One B-rep face of a CAD part: STEP entity #20.
In plain terms, the planar face has unit normal (1, 0, 0).
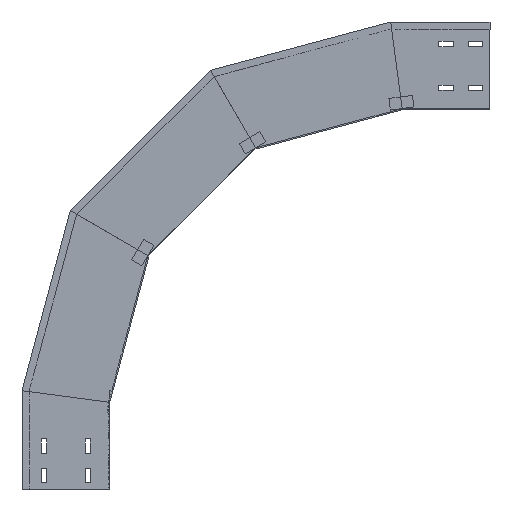
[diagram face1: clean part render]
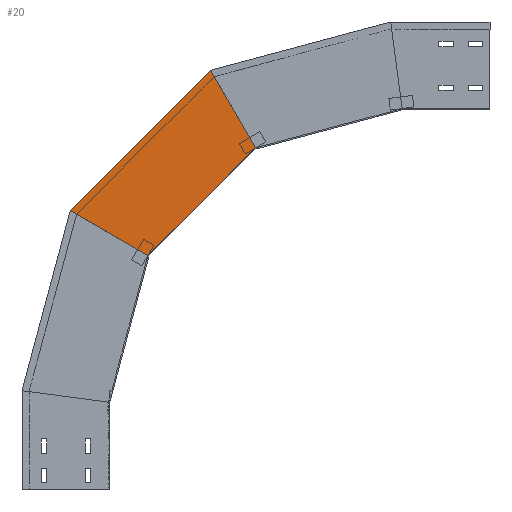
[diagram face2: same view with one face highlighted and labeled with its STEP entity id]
Its self-contained STEP definition (entity closure, numbers rounded to 3 decimals):
#20 = ADVANCED_FACE ( 'NONE', ( #899 ), #326, .T. ) ;
#69 = VECTOR ( 'NONE', #1328, 1000. ) ;
#89 = EDGE_CURVE ( 'NONE', #419, #1081, #347, .T. ) ;
#161 = CARTESIAN_POINT ( 'NONE',  ( 0., -129.979, 363.834 ) ) ;
#304 = CARTESIAN_POINT ( 'NONE',  ( 0., -250.175, 583.315 ) ) ;
#326 = PLANE ( 'NONE',  #1686 ) ;
#339 = DIRECTION ( 'NONE',  ( 1., 0., 0. ) ) ;
#347 = LINE ( 'NONE', #161, #1726 ) ;
#419 = VERTEX_POINT ( 'NONE', #2018 ) ;
#473 = EDGE_CURVE ( 'NONE', #1081, #1722, #1316, .T. ) ;
#825 = CARTESIAN_POINT ( 'NONE',  ( 0., -67.034, 400.175 ) ) ;
#899 = FACE_OUTER_BOUND ( 'NONE', #1931, .T. ) ;
#938 = ORIENTED_EDGE ( 'NONE', *, *, #89, .F. ) ;
#1081 = VERTEX_POINT ( 'NONE', #825 ) ;
#1151 = VECTOR ( 'NONE', #2013, 1000. ) ;
#1255 = EDGE_CURVE ( 'NONE', #419, #1511, #1787, .T. ) ;
#1316 = LINE ( 'NONE', #2109, #69 ) ;
#1328 = DIRECTION ( 'NONE',  ( 0., -0.707, 0.707 ) ) ;
#1434 = ORIENTED_EDGE ( 'NONE', *, *, #473, .F. ) ;
#1441 = CARTESIAN_POINT ( 'NONE',  ( 0., 70.365, 474.908 ) ) ;
#1498 = ORIENTED_EDGE ( 'NONE', *, *, #1255, .T. ) ;
#1511 = VERTEX_POINT ( 'NONE', #1518 ) ;
#1512 = LINE ( 'NONE', #2098, #1966 ) ;
#1518 = CARTESIAN_POINT ( 'NONE',  ( 0., -172.529, 717.802 ) ) ;
#1528 = ORIENTED_EDGE ( 'NONE', *, *, #2353, .T. ) ;
#1653 = DIRECTION ( 'NONE',  ( 0., 0., -1. ) ) ;
#1686 = AXIS2_PLACEMENT_3D ( 'NONE', #1837, #339, #1653 ) ;
#1722 = VERTEX_POINT ( 'NONE', #304 ) ;
#1726 = VECTOR ( 'NONE', #2416, 1000. ) ;
#1787 = LINE ( 'NONE', #1441, #1151 ) ;
#1837 = CARTESIAN_POINT ( 'NONE',  ( 0., -35.701, 368.842 ) ) ;
#1931 = EDGE_LOOP ( 'NONE', ( #1498, #1528, #1434, #938 ) ) ;
#1966 = VECTOR ( 'NONE', #2277, 1000. ) ;
#2013 = DIRECTION ( 'NONE',  ( 0., -0.707, 0.707 ) ) ;
#2018 = CARTESIAN_POINT ( 'NONE',  ( 0., 67.452, 477.821 ) ) ;
#2098 = CARTESIAN_POINT ( 'NONE',  ( 0., -289.426, 515.33 ) ) ;
#2109 = CARTESIAN_POINT ( 'NONE',  ( 0., -35.701, 368.842 ) ) ;
#2277 = DIRECTION ( 'NONE',  ( 0., -0.5, -0.866 ) ) ;
#2353 = EDGE_CURVE ( 'NONE', #1511, #1722, #1512, .T. ) ;
#2416 = DIRECTION ( 'NONE',  ( 0., -0.866, -0.5 ) ) ;
